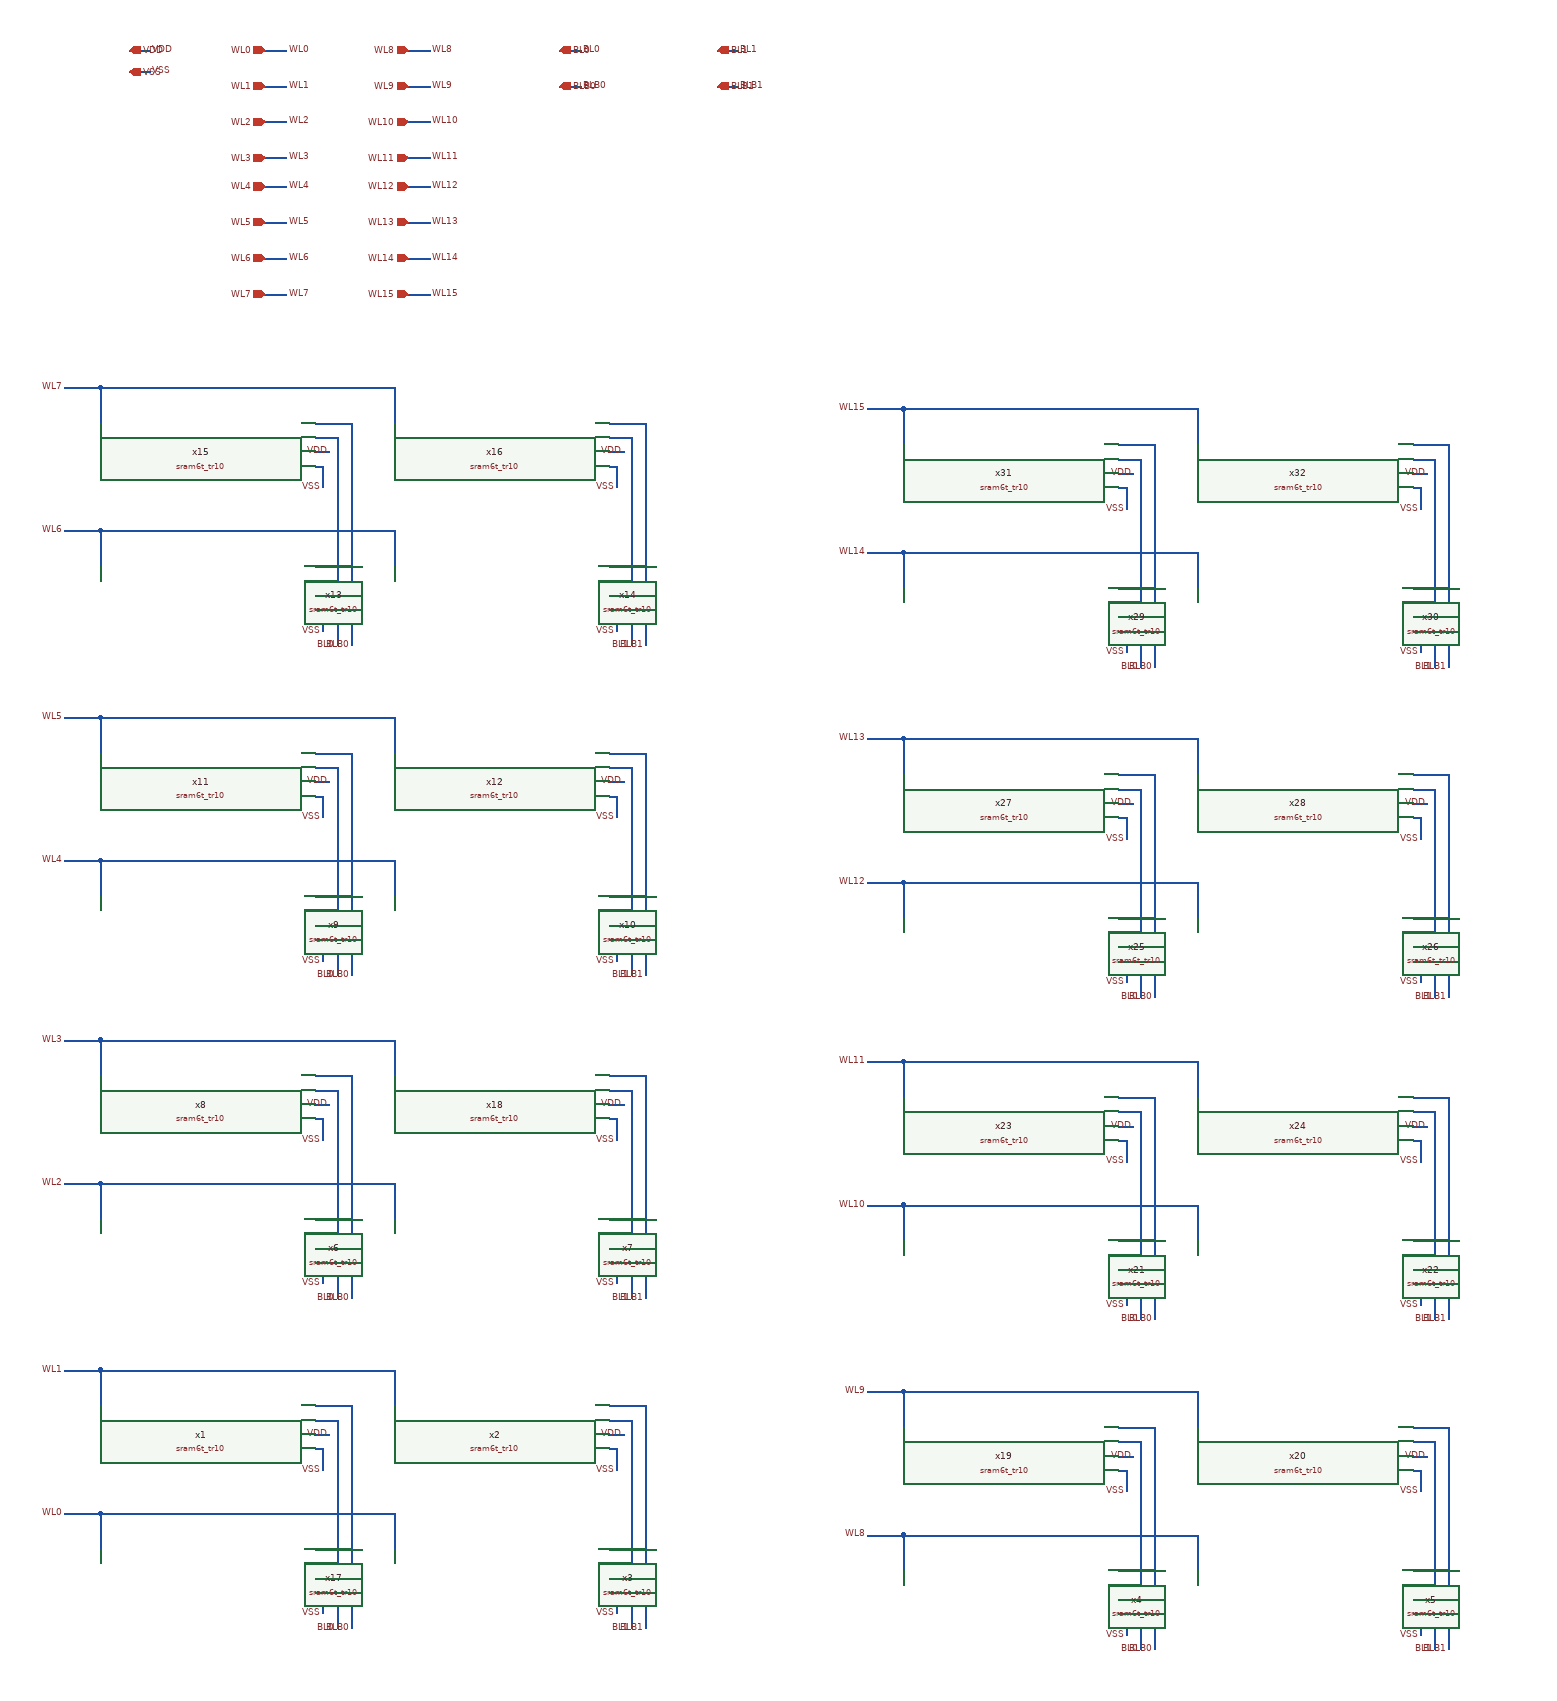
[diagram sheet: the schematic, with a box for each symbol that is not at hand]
v {xschem version=3.4.8RC file_version=1.3}
G {}
K {}
V {}
S {}
F {}
E {}
N 50 -560 50 -510 {lab=WL1}
N 50 -560 460 -560 {lab=WL1}
N 460 -560 460 -510 {lab=WL1}
N 0 -560 50 -560 {lab=WL1}
N 50 -360 50 -310 {lab=WL0}
N 50 -360 460 -360 {lab=WL0}
N 460 -360 460 -310 {lab=WL0}
N -0 -360 50 -360 {lab=WL0}
N 350 -490 380 -490 {lab=BL0}
N 380 -490 380 -200 {lab=BL0}
N 350 -290 380 -290 {lab=BL0}
N 350 -510 400 -510 {lab=BLB0}
N 400 -510 400 -200 {lab=BLB0}
N 350 -310 400 -310 {lab=BLB0}
N 760 -490 790 -490 {lab=BL1}
N 790 -490 790 -200 {lab=BL1}
N 760 -290 790 -290 {lab=BL1}
N 760 -510 810 -510 {lab=BLB1}
N 810 -510 810 -200 {lab=BLB1}
N 760 -310 810 -310 {lab=BLB1}
N 350 -270 370 -270 {lab=VDD}
N 350 -470 370 -470 {lab=VDD}
N 350 -450 360 -450 {lab=VSS}
N 360 -450 360 -420 {lab=VSS}
N 350 -250 360 -250 {lab=VSS}
N 360 -250 360 -220 {lab=VSS}
N 760 -450 770 -450 {lab=VSS}
N 770 -450 770 -420 {lab=VSS}
N 760 -250 770 -250 {lab=VSS}
N 770 -250 770 -220 {lab=VSS}
N 760 -470 780 -470 {lab=VDD}
N 760 -270 780 -270 {lab=VDD}
N 90 -2400 120 -2400 {lab=VDD}
N 280 -2400 310 -2400 {lab=WL0}
N 280 -2350 310 -2350 {lab=WL1}
N 690 -2400 720 -2400 {lab=BL0}
N 690 -2350 720 -2350 {lab=BLB0}
N 910 -2400 940 -2400 {lab=BL1}
N 910 -2350 940 -2350 {lab=BLB1}
N 50 -1020 50 -970 {lab=WL3}
N 50 -1020 460 -1020 {lab=WL3}
N 460 -1020 460 -970 {lab=WL3}
N 0 -1020 50 -1020 {lab=WL3}
N 50 -820 50 -770 {lab=WL2}
N 50 -820 460 -820 {lab=WL2}
N 460 -820 460 -770 {lab=WL2}
N 0 -820 50 -820 {lab=WL2}
N 350 -950 380 -950 {lab=BL0}
N 380 -950 380 -660 {lab=BL0}
N 350 -750 380 -750 {lab=BL0}
N 350 -970 400 -970 {lab=BLB0}
N 400 -970 400 -660 {lab=BLB0}
N 350 -770 400 -770 {lab=BLB0}
N 760 -950 790 -950 {lab=BL1}
N 790 -950 790 -660 {lab=BL1}
N 760 -750 790 -750 {lab=BL1}
N 760 -970 810 -970 {lab=BLB1}
N 810 -970 810 -660 {lab=BLB1}
N 760 -770 810 -770 {lab=BLB1}
N 350 -730 370 -730 {lab=VDD}
N 350 -930 370 -930 {lab=VDD}
N 350 -910 360 -910 {lab=VSS}
N 360 -910 360 -880 {lab=VSS}
N 350 -710 360 -710 {lab=VSS}
N 360 -710 360 -680 {lab=VSS}
N 760 -910 770 -910 {lab=VSS}
N 770 -910 770 -880 {lab=VSS}
N 760 -710 770 -710 {lab=VSS}
N 770 -710 770 -680 {lab=VSS}
N 760 -930 780 -930 {lab=VDD}
N 760 -730 780 -730 {lab=VDD}
N 50 -1470 50 -1420 {lab=WL5}
N 50 -1470 460 -1470 {lab=WL5}
N 460 -1470 460 -1420 {lab=WL5}
N 0 -1470 50 -1470 {lab=WL5}
N 50 -1270 50 -1220 {lab=WL4}
N 50 -1270 460 -1270 {lab=WL4}
N 460 -1270 460 -1220 {lab=WL4}
N 0 -1270 50 -1270 {lab=WL4}
N 350 -1400 380 -1400 {lab=BL0}
N 380 -1400 380 -1110 {lab=BL0}
N 350 -1200 380 -1200 {lab=BL0}
N 350 -1420 400 -1420 {lab=BLB0}
N 400 -1420 400 -1110 {lab=BLB0}
N 350 -1220 400 -1220 {lab=BLB0}
N 760 -1400 790 -1400 {lab=BL1}
N 790 -1400 790 -1110 {lab=BL1}
N 760 -1200 790 -1200 {lab=BL1}
N 760 -1420 810 -1420 {lab=BLB1}
N 810 -1420 810 -1110 {lab=BLB1}
N 760 -1220 810 -1220 {lab=BLB1}
N 350 -1180 370 -1180 {lab=VDD}
N 350 -1380 370 -1380 {lab=VDD}
N 350 -1360 360 -1360 {lab=VSS}
N 360 -1360 360 -1330 {lab=VSS}
N 350 -1160 360 -1160 {lab=VSS}
N 360 -1160 360 -1130 {lab=VSS}
N 760 -1360 770 -1360 {lab=VSS}
N 770 -1360 770 -1330 {lab=VSS}
N 760 -1160 770 -1160 {lab=VSS}
N 770 -1160 770 -1130 {lab=VSS}
N 760 -1380 780 -1380 {lab=VDD}
N 760 -1180 780 -1180 {lab=VDD}
N 50 -1930 50 -1880 {lab=WL7}
N 50 -1930 460 -1930 {lab=WL7}
N 460 -1930 460 -1880 {lab=WL7}
N 0 -1930 50 -1930 {lab=WL7}
N 50 -1730 50 -1680 {lab=WL6}
N 50 -1730 460 -1730 {lab=WL6}
N 460 -1730 460 -1680 {lab=WL6}
N 0 -1730 50 -1730 {lab=WL6}
N 350 -1860 380 -1860 {lab=BL0}
N 380 -1860 380 -1570 {lab=BL0}
N 350 -1660 380 -1660 {lab=BL0}
N 350 -1880 400 -1880 {lab=BLB0}
N 400 -1880 400 -1570 {lab=BLB0}
N 350 -1680 400 -1680 {lab=BLB0}
N 760 -1860 790 -1860 {lab=BL1}
N 790 -1860 790 -1570 {lab=BL1}
N 760 -1660 790 -1660 {lab=BL1}
N 760 -1880 810 -1880 {lab=BLB1}
N 810 -1880 810 -1570 {lab=BLB1}
N 760 -1680 810 -1680 {lab=BLB1}
N 350 -1640 370 -1640 {lab=VDD}
N 350 -1840 370 -1840 {lab=VDD}
N 350 -1820 360 -1820 {lab=VSS}
N 360 -1820 360 -1790 {lab=VSS}
N 350 -1620 360 -1620 {lab=VSS}
N 360 -1620 360 -1590 {lab=VSS}
N 760 -1820 770 -1820 {lab=VSS}
N 770 -1820 770 -1790 {lab=VSS}
N 760 -1620 770 -1620 {lab=VSS}
N 770 -1620 770 -1590 {lab=VSS}
N 760 -1840 780 -1840 {lab=VDD}
N 760 -1640 780 -1640 {lab=VDD}
N 280 -2300 310 -2300 {lab=WL2}
N 280 -2250 310 -2250 {lab=WL3}
N 280 -2210 310 -2210 {lab=WL4}
N 280 -2160 310 -2160 {lab=WL5}
N 280 -2110 310 -2110 {lab=WL6}
N 280 -2060 310 -2060 {lab=WL7}
N 1170 -530 1170 -480 {lab=WL1}
N 1170 -530 1580 -530 {lab=WL1}
N 1580 -530 1580 -480 {lab=WL1}
N 1120 -530 1170 -530 {lab=WL1}
N 1170 -330 1170 -280 {lab=WL0}
N 1170 -330 1580 -330 {lab=WL0}
N 1580 -330 1580 -280 {lab=WL0}
N 1120 -330 1170 -330 {lab=WL0}
N 1470 -460 1500 -460 {lab=BL0}
N 1500 -460 1500 -170 {lab=BL0}
N 1470 -260 1500 -260 {lab=BL0}
N 1470 -480 1520 -480 {lab=BLB0}
N 1520 -480 1520 -170 {lab=BLB0}
N 1470 -280 1520 -280 {lab=BLB0}
N 1880 -460 1910 -460 {lab=BL1}
N 1910 -460 1910 -170 {lab=BL1}
N 1880 -260 1910 -260 {lab=BL1}
N 1880 -480 1930 -480 {lab=BLB1}
N 1930 -480 1930 -170 {lab=BLB1}
N 1880 -280 1930 -280 {lab=BLB1}
N 1470 -240 1490 -240 {lab=VDD}
N 1470 -440 1490 -440 {lab=VDD}
N 1470 -420 1480 -420 {lab=VSS}
N 1480 -420 1480 -390 {lab=VSS}
N 1470 -220 1480 -220 {lab=VSS}
N 1480 -220 1480 -190 {lab=VSS}
N 1880 -420 1890 -420 {lab=VSS}
N 1890 -420 1890 -390 {lab=VSS}
N 1880 -220 1890 -220 {lab=VSS}
N 1890 -220 1890 -190 {lab=VSS}
N 1880 -440 1900 -440 {lab=VDD}
N 1880 -240 1900 -240 {lab=VDD}
N 1170 -990 1170 -940 {lab=WL3}
N 1170 -990 1580 -990 {lab=WL3}
N 1580 -990 1580 -940 {lab=WL3}
N 1120 -990 1170 -990 {lab=WL3}
N 1170 -790 1170 -740 {lab=WL2}
N 1170 -790 1580 -790 {lab=WL2}
N 1580 -790 1580 -740 {lab=WL2}
N 1120 -790 1170 -790 {lab=WL2}
N 1470 -920 1500 -920 {lab=BL0}
N 1500 -920 1500 -630 {lab=BL0}
N 1470 -720 1500 -720 {lab=BL0}
N 1470 -940 1520 -940 {lab=BLB0}
N 1520 -940 1520 -630 {lab=BLB0}
N 1470 -740 1520 -740 {lab=BLB0}
N 1880 -920 1910 -920 {lab=BL1}
N 1910 -920 1910 -630 {lab=BL1}
N 1880 -720 1910 -720 {lab=BL1}
N 1880 -940 1930 -940 {lab=BLB1}
N 1930 -940 1930 -630 {lab=BLB1}
N 1880 -740 1930 -740 {lab=BLB1}
N 1470 -700 1490 -700 {lab=VDD}
N 1470 -900 1490 -900 {lab=VDD}
N 1470 -880 1480 -880 {lab=VSS}
N 1480 -880 1480 -850 {lab=VSS}
N 1470 -680 1480 -680 {lab=VSS}
N 1480 -680 1480 -650 {lab=VSS}
N 1880 -880 1890 -880 {lab=VSS}
N 1890 -880 1890 -850 {lab=VSS}
N 1880 -680 1890 -680 {lab=VSS}
N 1890 -680 1890 -650 {lab=VSS}
N 1880 -900 1900 -900 {lab=VDD}
N 1880 -700 1900 -700 {lab=VDD}
N 1170 -1440 1170 -1390 {lab=WL5}
N 1170 -1440 1580 -1440 {lab=WL5}
N 1580 -1440 1580 -1390 {lab=WL5}
N 1120 -1440 1170 -1440 {lab=WL5}
N 1170 -1240 1170 -1190 {lab=WL4}
N 1170 -1240 1580 -1240 {lab=WL4}
N 1580 -1240 1580 -1190 {lab=WL4}
N 1120 -1240 1170 -1240 {lab=WL4}
N 1470 -1370 1500 -1370 {lab=BL0}
N 1500 -1370 1500 -1080 {lab=BL0}
N 1470 -1170 1500 -1170 {lab=BL0}
N 1470 -1390 1520 -1390 {lab=BLB0}
N 1520 -1390 1520 -1080 {lab=BLB0}
N 1470 -1190 1520 -1190 {lab=BLB0}
N 1880 -1370 1910 -1370 {lab=BL1}
N 1910 -1370 1910 -1080 {lab=BL1}
N 1880 -1170 1910 -1170 {lab=BL1}
N 1880 -1390 1930 -1390 {lab=BLB1}
N 1930 -1390 1930 -1080 {lab=BLB1}
N 1880 -1190 1930 -1190 {lab=BLB1}
N 1470 -1150 1490 -1150 {lab=VDD}
N 1470 -1350 1490 -1350 {lab=VDD}
N 1470 -1330 1480 -1330 {lab=VSS}
N 1480 -1330 1480 -1300 {lab=VSS}
N 1470 -1130 1480 -1130 {lab=VSS}
N 1480 -1130 1480 -1100 {lab=VSS}
N 1880 -1330 1890 -1330 {lab=VSS}
N 1890 -1330 1890 -1300 {lab=VSS}
N 1880 -1130 1890 -1130 {lab=VSS}
N 1890 -1130 1890 -1100 {lab=VSS}
N 1880 -1350 1900 -1350 {lab=VDD}
N 1880 -1150 1900 -1150 {lab=VDD}
N 1170 -1900 1170 -1850 {lab=WL7}
N 1170 -1900 1580 -1900 {lab=WL7}
N 1580 -1900 1580 -1850 {lab=WL7}
N 1120 -1900 1170 -1900 {lab=WL7}
N 1170 -1700 1170 -1650 {lab=WL6}
N 1170 -1700 1580 -1700 {lab=WL6}
N 1580 -1700 1580 -1650 {lab=WL6}
N 1120 -1700 1170 -1700 {lab=WL6}
N 1470 -1830 1500 -1830 {lab=BL0}
N 1500 -1830 1500 -1540 {lab=BL0}
N 1470 -1630 1500 -1630 {lab=BL0}
N 1470 -1850 1520 -1850 {lab=BLB0}
N 1520 -1850 1520 -1540 {lab=BLB0}
N 1470 -1650 1520 -1650 {lab=BLB0}
N 1880 -1830 1910 -1830 {lab=BL1}
N 1910 -1830 1910 -1540 {lab=BL1}
N 1880 -1630 1910 -1630 {lab=BL1}
N 1880 -1850 1930 -1850 {lab=BLB1}
N 1930 -1850 1930 -1540 {lab=BLB1}
N 1880 -1650 1930 -1650 {lab=BLB1}
N 1470 -1610 1490 -1610 {lab=VDD}
N 1470 -1810 1490 -1810 {lab=VDD}
N 1470 -1790 1480 -1790 {lab=VSS}
N 1480 -1790 1480 -1760 {lab=VSS}
N 1470 -1590 1480 -1590 {lab=VSS}
N 1480 -1590 1480 -1560 {lab=VSS}
N 1880 -1790 1890 -1790 {lab=VSS}
N 1890 -1790 1890 -1760 {lab=VSS}
N 1880 -1590 1890 -1590 {lab=VSS}
N 1890 -1590 1890 -1560 {lab=VSS}
N 1880 -1810 1900 -1810 {lab=VDD}
N 1880 -1610 1900 -1610 {lab=VDD}
N 90 -2370 120 -2370 {lab=VDD}
N 480 -2400 510 -2400 {lab=WL0}
N 480 -2350 510 -2350 {lab=WL1}
N 480 -2300 510 -2300 {lab=WL2}
N 480 -2250 510 -2250 {lab=WL3}
N 480 -2210 510 -2210 {lab=WL4}
N 480 -2160 510 -2160 {lab=WL5}
N 480 -2110 510 -2110 {lab=WL6}
N 480 -2060 510 -2060 {lab=WL7}
C {devices/lab_pin.sym} 370 -470 1 1 {name=p1 sig_type=std_logic lab=VDD}
C {devices/lab_pin.sym} 780 -470 1 1 {name=p2 sig_type=std_logic lab=VDD}
C {devices/lab_pin.sym} 370 -270 1 1 {name=p3 sig_type=std_logic lab=VDD}
C {devices/lab_pin.sym} 780 -270 1 1 {name=p4 sig_type=std_logic lab=VDD}
C {devices/lab_pin.sym} 0 -560 0 0 {name=p5 sig_type=std_logic lab=WL1}
C {devices/lab_pin.sym} 0 -360 0 0 {name=p6 sig_type=std_logic lab=WL0}
C {devices/lab_pin.sym} 380 -200 1 1 {name=p7 sig_type=std_logic lab=BL0}
C {devices/lab_pin.sym} 400 -200 1 1 {name=p8 sig_type=std_logic lab=BLB0}
C {devices/lab_pin.sym} 790 -200 1 1 {name=p9 sig_type=std_logic lab=BL1}
C {devices/lab_pin.sym} 810 -200 1 1 {name=p10 sig_type=std_logic lab=BLB1}
C {devices/lab_pin.sym} 360 -420 1 1 {name=p11 sig_type=std_logic lab=VSS}
C {devices/lab_pin.sym} 770 -420 1 1 {name=p12 sig_type=std_logic lab=VSS}
C {devices/lab_pin.sym} 360 -220 1 1 {name=p13 sig_type=std_logic lab=VSS}
C {devices/lab_pin.sym} 770 -220 1 1 {name=p14 sig_type=std_logic lab=VSS}
C {devices/iopin.sym} 90 -2400 0 1 {name=p15 lab=VDD}
C {devices/iopin.sym} 690 -2400 0 1 {name=p19 lab=BL0}
C {devices/iopin.sym} 690 -2350 0 1 {name=p20 lab=BLB0}
C {devices/iopin.sym} 910 -2400 0 1 {name=p21 lab=BL1}
C {devices/iopin.sym} 910 -2350 0 1 {name=p22 lab=BLB1}
C {devices/lab_pin.sym} 120 -2400 0 1 {name=p23 sig_type=std_logic lab=VDD}
C {devices/lab_pin.sym} 310 -2400 0 1 {name=p25 sig_type=std_logic lab=WL0}
C {devices/lab_pin.sym} 310 -2350 0 1 {name=p26 sig_type=std_logic lab=WL1}
C {devices/lab_pin.sym} 720 -2400 0 1 {name=p27 sig_type=std_logic lab=BL0}
C {devices/lab_pin.sym} 720 -2350 0 1 {name=p28 sig_type=std_logic lab=BLB0}
C {devices/lab_pin.sym} 940 -2400 0 1 {name=p29 sig_type=std_logic lab=BL1}
C {devices/lab_pin.sym} 940 -2350 0 1 {name=p30 sig_type=std_logic lab=BLB1}
C {devices/ipin.sym} 280 -2400 0 0 {name=p17 lab=WL0}
C {devices/ipin.sym} 280 -2350 0 0 {name=p18 lab=WL1}
C {devices/lab_pin.sym} 370 -930 1 1 {name=p31 sig_type=std_logic lab=VDD}
C {devices/lab_pin.sym} 780 -930 1 1 {name=p32 sig_type=std_logic lab=VDD}
C {devices/lab_pin.sym} 370 -730 1 1 {name=p33 sig_type=std_logic lab=VDD}
C {devices/lab_pin.sym} 780 -730 1 1 {name=p34 sig_type=std_logic lab=VDD}
C {devices/lab_pin.sym} 0 -1020 0 0 {name=p35 sig_type=std_logic lab=WL3}
C {devices/lab_pin.sym} 0 -820 0 0 {name=p36 sig_type=std_logic lab=WL2}
C {devices/lab_pin.sym} 380 -660 1 1 {name=p37 sig_type=std_logic lab=BL0}
C {devices/lab_pin.sym} 400 -660 1 1 {name=p38 sig_type=std_logic lab=BLB0}
C {devices/lab_pin.sym} 790 -660 1 1 {name=p39 sig_type=std_logic lab=BL1}
C {devices/lab_pin.sym} 810 -660 1 1 {name=p40 sig_type=std_logic lab=BLB1}
C {devices/lab_pin.sym} 360 -880 1 1 {name=p41 sig_type=std_logic lab=VSS}
C {devices/lab_pin.sym} 770 -880 1 1 {name=p42 sig_type=std_logic lab=VSS}
C {devices/lab_pin.sym} 360 -680 1 1 {name=p43 sig_type=std_logic lab=VSS}
C {devices/lab_pin.sym} 770 -680 1 1 {name=p44 sig_type=std_logic lab=VSS}
C {devices/lab_pin.sym} 370 -1380 1 1 {name=p45 sig_type=std_logic lab=VDD}
C {devices/lab_pin.sym} 780 -1380 1 1 {name=p46 sig_type=std_logic lab=VDD}
C {devices/lab_pin.sym} 370 -1180 1 1 {name=p47 sig_type=std_logic lab=VDD}
C {devices/lab_pin.sym} 780 -1180 1 1 {name=p48 sig_type=std_logic lab=VDD}
C {devices/lab_pin.sym} 0 -1470 0 0 {name=p49 sig_type=std_logic lab=WL5}
C {devices/lab_pin.sym} 0 -1270 0 0 {name=p50 sig_type=std_logic lab=WL4}
C {devices/lab_pin.sym} 380 -1110 1 1 {name=p51 sig_type=std_logic lab=BL0}
C {devices/lab_pin.sym} 400 -1110 1 1 {name=p52 sig_type=std_logic lab=BLB0}
C {devices/lab_pin.sym} 790 -1110 1 1 {name=p53 sig_type=std_logic lab=BL1}
C {devices/lab_pin.sym} 810 -1110 1 1 {name=p54 sig_type=std_logic lab=BLB1}
C {devices/lab_pin.sym} 360 -1330 1 1 {name=p55 sig_type=std_logic lab=VSS}
C {devices/lab_pin.sym} 770 -1330 1 1 {name=p56 sig_type=std_logic lab=VSS}
C {devices/lab_pin.sym} 360 -1130 1 1 {name=p57 sig_type=std_logic lab=VSS}
C {devices/lab_pin.sym} 770 -1130 1 1 {name=p58 sig_type=std_logic lab=VSS}
C {devices/lab_pin.sym} 370 -1840 1 1 {name=p59 sig_type=std_logic lab=VDD}
C {devices/lab_pin.sym} 780 -1840 1 1 {name=p60 sig_type=std_logic lab=VDD}
C {devices/lab_pin.sym} 370 -1640 1 1 {name=p61 sig_type=std_logic lab=VDD}
C {devices/lab_pin.sym} 780 -1640 1 1 {name=p62 sig_type=std_logic lab=VDD}
C {devices/lab_pin.sym} 0 -1930 0 0 {name=p63 sig_type=std_logic lab=WL7}
C {devices/lab_pin.sym} 0 -1730 0 0 {name=p64 sig_type=std_logic lab=WL6}
C {devices/lab_pin.sym} 380 -1570 1 1 {name=p65 sig_type=std_logic lab=BL0}
C {devices/lab_pin.sym} 400 -1570 1 1 {name=p66 sig_type=std_logic lab=BLB0}
C {devices/lab_pin.sym} 790 -1570 1 1 {name=p67 sig_type=std_logic lab=BL1}
C {devices/lab_pin.sym} 810 -1570 1 1 {name=p68 sig_type=std_logic lab=BLB1}
C {devices/lab_pin.sym} 360 -1790 1 1 {name=p69 sig_type=std_logic lab=VSS}
C {devices/lab_pin.sym} 770 -1790 1 1 {name=p70 sig_type=std_logic lab=VSS}
C {devices/lab_pin.sym} 360 -1590 1 1 {name=p71 sig_type=std_logic lab=VSS}
C {devices/lab_pin.sym} 770 -1590 1 1 {name=p72 sig_type=std_logic lab=VSS}
C {devices/lab_pin.sym} 310 -2300 0 1 {name=p129 sig_type=std_logic lab=WL2}
C {devices/lab_pin.sym} 310 -2250 0 1 {name=p130 sig_type=std_logic lab=WL3}
C {devices/ipin.sym} 280 -2300 0 0 {name=p131 lab=WL2}
C {devices/ipin.sym} 280 -2250 0 0 {name=p132 lab=WL3}
C {devices/lab_pin.sym} 310 -2210 0 1 {name=p133 sig_type=std_logic lab=WL4}
C {devices/lab_pin.sym} 310 -2160 0 1 {name=p134 sig_type=std_logic lab=WL5}
C {devices/ipin.sym} 280 -2210 0 0 {name=p135 lab=WL4}
C {devices/ipin.sym} 280 -2160 0 0 {name=p136 lab=WL5}
C {devices/lab_pin.sym} 310 -2110 0 1 {name=p137 sig_type=std_logic lab=WL6}
C {devices/lab_pin.sym} 310 -2060 0 1 {name=p138 sig_type=std_logic lab=WL7}
C {devices/ipin.sym} 280 -2110 0 0 {name=p139 lab=WL6}
C {devices/ipin.sym} 280 -2060 0 0 {name=p140 lab=WL7}
C {sram6t_tr10.sym} 200 -280 0 0 {name=x17}
C {sram6t_tr10.sym} 610 -280 0 0 {name=x3}
C {sram6t_tr10.sym} 200 -480 0 0 {name=x1}
C {sram6t_tr10.sym} 610 -480 0 0 {name=x2}
C {sram6t_tr10.sym} 200 -740 0 0 {name=x6}
C {sram6t_tr10.sym} 610 -740 0 0 {name=x7}
C {sram6t_tr10.sym} 200 -940 0 0 {name=x8}
C {sram6t_tr10.sym} 610 -940 0 0 {name=x18}
C {sram6t_tr10.sym} 200 -1190 0 0 {name=x9}
C {sram6t_tr10.sym} 610 -1190 0 0 {name=x10}
C {sram6t_tr10.sym} 200 -1390 0 0 {name=x11}
C {sram6t_tr10.sym} 610 -1390 0 0 {name=x12}
C {sram6t_tr10.sym} 200 -1650 0 0 {name=x13}
C {sram6t_tr10.sym} 610 -1650 0 0 {name=x14}
C {sram6t_tr10.sym} 200 -1850 0 0 {name=x15}
C {sram6t_tr10.sym} 610 -1850 0 0 {name=x16}
C {devices/lab_pin.sym} 1490 -440 1 1 {name=p73 sig_type=std_logic lab=VDD}
C {devices/lab_pin.sym} 1900 -440 1 1 {name=p74 sig_type=std_logic lab=VDD}
C {devices/lab_pin.sym} 1490 -240 1 1 {name=p75 sig_type=std_logic lab=VDD}
C {devices/lab_pin.sym} 1900 -240 1 1 {name=p76 sig_type=std_logic lab=VDD}
C {devices/lab_pin.sym} 1120 -530 0 0 {name=p77 sig_type=std_logic lab=WL9}
C {devices/lab_pin.sym} 1120 -330 0 0 {name=p78 sig_type=std_logic lab=WL8}
C {devices/lab_pin.sym} 1500 -170 1 1 {name=p79 sig_type=std_logic lab=BL0}
C {devices/lab_pin.sym} 1520 -170 1 1 {name=p80 sig_type=std_logic lab=BLB0}
C {devices/lab_pin.sym} 1910 -170 1 1 {name=p81 sig_type=std_logic lab=BL1}
C {devices/lab_pin.sym} 1930 -170 1 1 {name=p82 sig_type=std_logic lab=BLB1}
C {devices/lab_pin.sym} 1480 -390 1 1 {name=p83 sig_type=std_logic lab=VSS}
C {devices/lab_pin.sym} 1890 -390 1 1 {name=p84 sig_type=std_logic lab=VSS}
C {devices/lab_pin.sym} 1480 -190 1 1 {name=p85 sig_type=std_logic lab=VSS}
C {devices/lab_pin.sym} 1890 -190 1 1 {name=p86 sig_type=std_logic lab=VSS}
C {devices/lab_pin.sym} 1490 -900 1 1 {name=p87 sig_type=std_logic lab=VDD}
C {devices/lab_pin.sym} 1900 -900 1 1 {name=p88 sig_type=std_logic lab=VDD}
C {devices/lab_pin.sym} 1490 -700 1 1 {name=p89 sig_type=std_logic lab=VDD}
C {devices/lab_pin.sym} 1900 -700 1 1 {name=p90 sig_type=std_logic lab=VDD}
C {devices/lab_pin.sym} 1120 -990 0 0 {name=p91 sig_type=std_logic lab=WL11}
C {devices/lab_pin.sym} 1120 -790 0 0 {name=p92 sig_type=std_logic lab=WL10}
C {devices/lab_pin.sym} 1500 -630 1 1 {name=p93 sig_type=std_logic lab=BL0}
C {devices/lab_pin.sym} 1520 -630 1 1 {name=p94 sig_type=std_logic lab=BLB0}
C {devices/lab_pin.sym} 1910 -630 1 1 {name=p95 sig_type=std_logic lab=BL1}
C {devices/lab_pin.sym} 1930 -630 1 1 {name=p96 sig_type=std_logic lab=BLB1}
C {devices/lab_pin.sym} 1480 -850 1 1 {name=p97 sig_type=std_logic lab=VSS}
C {devices/lab_pin.sym} 1890 -850 1 1 {name=p98 sig_type=std_logic lab=VSS}
C {devices/lab_pin.sym} 1480 -650 1 1 {name=p99 sig_type=std_logic lab=VSS}
C {devices/lab_pin.sym} 1890 -650 1 1 {name=p100 sig_type=std_logic lab=VSS}
C {devices/lab_pin.sym} 1490 -1350 1 1 {name=p101 sig_type=std_logic lab=VDD}
C {devices/lab_pin.sym} 1900 -1350 1 1 {name=p102 sig_type=std_logic lab=VDD}
C {devices/lab_pin.sym} 1490 -1150 1 1 {name=p103 sig_type=std_logic lab=VDD}
C {devices/lab_pin.sym} 1900 -1150 1 1 {name=p104 sig_type=std_logic lab=VDD}
C {devices/lab_pin.sym} 1120 -1440 0 0 {name=p105 sig_type=std_logic lab=WL13}
C {devices/lab_pin.sym} 1120 -1240 0 0 {name=p106 sig_type=std_logic lab=WL12}
C {devices/lab_pin.sym} 1500 -1080 1 1 {name=p107 sig_type=std_logic lab=BL0}
C {devices/lab_pin.sym} 1520 -1080 1 1 {name=p108 sig_type=std_logic lab=BLB0}
C {devices/lab_pin.sym} 1910 -1080 1 1 {name=p109 sig_type=std_logic lab=BL1}
C {devices/lab_pin.sym} 1930 -1080 1 1 {name=p110 sig_type=std_logic lab=BLB1}
C {devices/lab_pin.sym} 1480 -1300 1 1 {name=p111 sig_type=std_logic lab=VSS}
C {devices/lab_pin.sym} 1890 -1300 1 1 {name=p112 sig_type=std_logic lab=VSS}
C {devices/lab_pin.sym} 1480 -1100 1 1 {name=p113 sig_type=std_logic lab=VSS}
C {devices/lab_pin.sym} 1890 -1100 1 1 {name=p114 sig_type=std_logic lab=VSS}
C {devices/lab_pin.sym} 1490 -1810 1 1 {name=p115 sig_type=std_logic lab=VDD}
C {devices/lab_pin.sym} 1900 -1810 1 1 {name=p116 sig_type=std_logic lab=VDD}
C {devices/lab_pin.sym} 1490 -1610 1 1 {name=p117 sig_type=std_logic lab=VDD}
C {devices/lab_pin.sym} 1900 -1610 1 1 {name=p118 sig_type=std_logic lab=VDD}
C {devices/lab_pin.sym} 1120 -1900 0 0 {name=p119 sig_type=std_logic lab=WL15}
C {devices/lab_pin.sym} 1120 -1700 0 0 {name=p120 sig_type=std_logic lab=WL14}
C {devices/lab_pin.sym} 1500 -1540 1 1 {name=p121 sig_type=std_logic lab=BL0}
C {devices/lab_pin.sym} 1520 -1540 1 1 {name=p122 sig_type=std_logic lab=BLB0}
C {devices/lab_pin.sym} 1910 -1540 1 1 {name=p123 sig_type=std_logic lab=BL1}
C {devices/lab_pin.sym} 1930 -1540 1 1 {name=p124 sig_type=std_logic lab=BLB1}
C {devices/lab_pin.sym} 1480 -1760 1 1 {name=p125 sig_type=std_logic lab=VSS}
C {devices/lab_pin.sym} 1890 -1760 1 1 {name=p126 sig_type=std_logic lab=VSS}
C {devices/lab_pin.sym} 1480 -1560 1 1 {name=p127 sig_type=std_logic lab=VSS}
C {devices/lab_pin.sym} 1890 -1560 1 1 {name=p128 sig_type=std_logic lab=VSS}
C {sram6t_tr10.sym} 1320 -250 0 0 {name=x4}
C {sram6t_tr10.sym} 1730 -250 0 0 {name=x5}
C {sram6t_tr10.sym} 1320 -450 0 0 {name=x19}
C {sram6t_tr10.sym} 1730 -450 0 0 {name=x20}
C {sram6t_tr10.sym} 1320 -710 0 0 {name=x21}
C {sram6t_tr10.sym} 1730 -710 0 0 {name=x22}
C {sram6t_tr10.sym} 1320 -910 0 0 {name=x23}
C {sram6t_tr10.sym} 1730 -910 0 0 {name=x24}
C {sram6t_tr10.sym} 1320 -1160 0 0 {name=x25}
C {sram6t_tr10.sym} 1730 -1160 0 0 {name=x26}
C {sram6t_tr10.sym} 1320 -1360 0 0 {name=x27}
C {sram6t_tr10.sym} 1730 -1360 0 0 {name=x28}
C {sram6t_tr10.sym} 1320 -1620 0 0 {name=x29}
C {sram6t_tr10.sym} 1730 -1620 0 0 {name=x30}
C {sram6t_tr10.sym} 1320 -1820 0 0 {name=x31}
C {sram6t_tr10.sym} 1730 -1820 0 0 {name=x32}
C {devices/iopin.sym} 90 -2370 0 1 {name=p141 lab=VSS}
C {devices/lab_pin.sym} 120 -2370 0 1 {name=p142 sig_type=std_logic lab=VSS}
C {devices/lab_pin.sym} 510 -2400 0 1 {name=p16 sig_type=std_logic lab=WL8}
C {devices/lab_pin.sym} 510 -2350 0 1 {name=p24 sig_type=std_logic lab=WL9}
C {devices/ipin.sym} 480 -2400 0 0 {name=p143 lab=WL8}
C {devices/ipin.sym} 480 -2350 0 0 {name=p144 lab=WL9}
C {devices/lab_pin.sym} 510 -2300 0 1 {name=p145 sig_type=std_logic lab=WL10}
C {devices/lab_pin.sym} 510 -2250 0 1 {name=p146 sig_type=std_logic lab=WL11}
C {devices/ipin.sym} 480 -2300 0 0 {name=p147 lab=WL10}
C {devices/ipin.sym} 480 -2250 0 0 {name=p148 lab=WL11}
C {devices/lab_pin.sym} 510 -2210 0 1 {name=p149 sig_type=std_logic lab=WL12}
C {devices/lab_pin.sym} 510 -2160 0 1 {name=p150 sig_type=std_logic lab=WL13}
C {devices/ipin.sym} 480 -2210 0 0 {name=p151 lab=WL12}
C {devices/ipin.sym} 480 -2160 0 0 {name=p152 lab=WL13}
C {devices/lab_pin.sym} 510 -2110 0 1 {name=p153 sig_type=std_logic lab=WL14}
C {devices/lab_pin.sym} 510 -2060 0 1 {name=p154 sig_type=std_logic lab=WL15}
C {devices/ipin.sym} 480 -2110 0 0 {name=p155 lab=WL14}
C {devices/ipin.sym} 480 -2060 0 0 {name=p156 lab=WL15}
